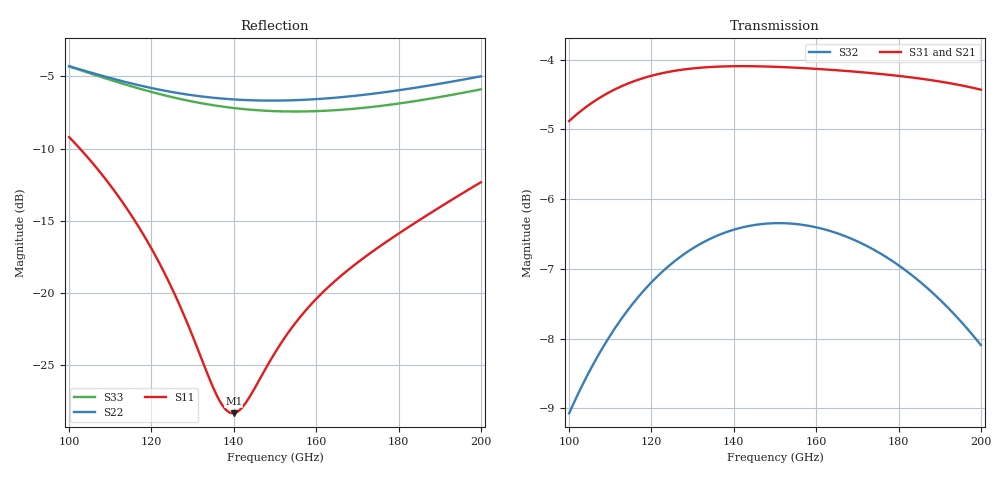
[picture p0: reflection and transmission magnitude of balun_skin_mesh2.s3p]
! Created with skrf 2.2.0 (http://scikit-rf.org).
# GHz S DB R 50.0
! Port[1] = P1
! Port[2] = P2
! Port[3] = P3
!freq dBS11 angS11 dBS12 angS12 dBS13 angS13
! dBS21 angS21 dBS22 angS22 dBS23 angS23
! dBS31 angS31 dBS32 angS32 dBS33 angS33
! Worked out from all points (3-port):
!   101 points, 100 GHz to 200 GHz, reference 50 ohm
!   strongest paths, dB at 100 GHz, 125 GHz, 150 GHz, 175 GHz, 200 GHz:
!     S31: -4.9, -4.2, -4.1, -4.2, -4.4
!     S21: -4.6, -4.0, -4.1, -4.4, -4.8
!     S32: -9.1, -6.9, -6.3, -6.8, -8.1
!   lowest |S11| = -28.4 dB at 140 GHz (marker M1), VSWR 1.08, Z = 46.4 + j0.63 ohm
!   |S11| at or under -10 dB: 102.6 GHz to end of sweep
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100  -9.21 129.4  -4.60 -13.1  -4.88 163.1
     -4.60 -13.1  -4.29 59.6  -9.07 90.2
     -4.88 163.1  -9.07 90.2  -4.31 49.1
118  -15.95 112.4  -4.09 -40.7  -4.26 133.7
     -4.09 -40.7  -5.68 43.9  -7.32 62.7
     -4.26 133.7  -7.32 62.7  -5.92 30.7
126  -20.32 113.2  -4.02 -52.0  -4.16 121.7
     -4.02 -52.0  -6.13 38.0  -6.87 51.4
     -4.16 121.7  -6.87 51.4  -6.50 23.8
136  -27.19 141.8  -4.02 -65.2  -4.10 107.5
     -4.02 -65.2  -6.51 30.9  -6.52 38.0
     -4.10 107.5  -6.52 38.0  -7.04 15.9
140  -28.35 169.8  -4.03 -70.4  -4.09 102.0
     -4.03 -70.4  -6.60 28.1  -6.44 32.8
     -4.09 102.0  -6.44 32.8  -7.19 12.8
143  -27.59 -170.6  -4.05 -74.1  -4.09 98.0
     -4.05 -74.1  -6.64 25.9  -6.39 29.0
     -4.09 98.0  -6.39 29.0  -7.28 10.6
150  -24.15 -146.6  -4.09 -82.7  -4.10 88.8
     -4.09 -82.7  -6.68 20.9  -6.34 20.2
     -4.10 88.8  -6.34 20.2  -7.41 5.3
167  -18.59 -135.0  -4.26 -103.1  -4.16 67.2
     -4.26 -103.1  -6.42 7.8  -6.53 -0.2
     -4.16 67.2  -6.53 -0.2  -7.30 -7.7
185  -14.97 -135.1  -4.52 -124.3  -4.27 44.7
     -4.52 -124.3  -5.74 -7.7  -7.17 -21.3
     -4.27 44.7  -7.17 -21.3  -6.67 -22.7
200  -12.34 -139.9  -4.85 -142.5  -4.43 25.6
     -4.85 -142.5  -5.00 -21.9  -8.09 -38.8
     -4.43 25.6  -8.09 -38.8  -5.90 -36.4
